One B-rep face of a CAD part: STEP entity #228.
In plain terms, the cylindrical face has radius 5 mm (diameter 10 mm), a partial arc.
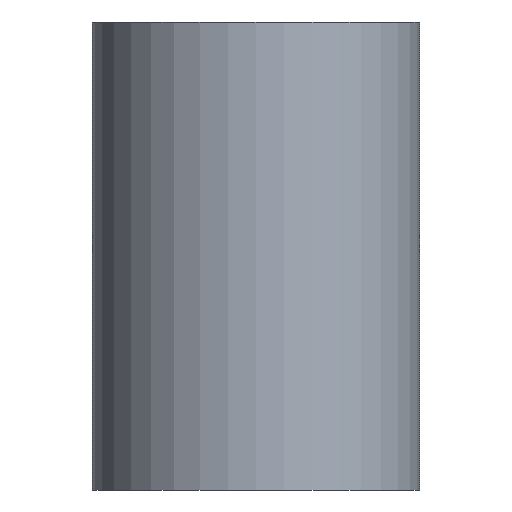
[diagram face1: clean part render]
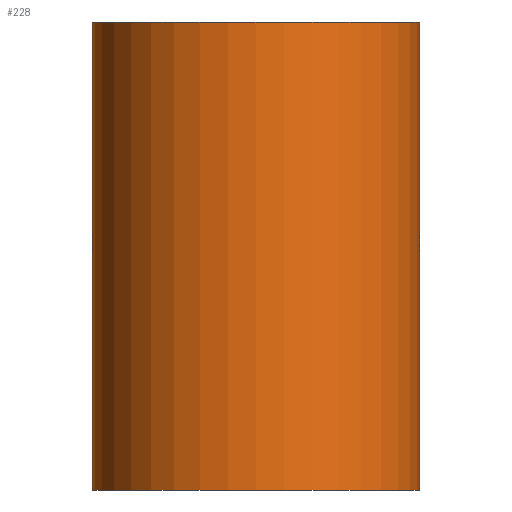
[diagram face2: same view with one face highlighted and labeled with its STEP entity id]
Its self-contained STEP definition (entity closure, numbers rounded to 3 decimals):
#44 = PLANE('',#45);
#45 = AXIS2_PLACEMENT_3D('',#46,#47,#48);
#46 = CARTESIAN_POINT('',(-22.5,5.,0.));
#47 = DIRECTION('',(0.,1.,0.));
#48 = DIRECTION('',(1.,0.,0.));
#73 = PLANE('',#74);
#74 = AXIS2_PLACEMENT_3D('',#75,#76,#77);
#75 = CARTESIAN_POINT('',(0.,0.,14.3));
#76 = DIRECTION('',(0.,0.,1.));
#77 = DIRECTION('',(1.,0.,-0.));
#105 = PLANE('',#106);
#106 = AXIS2_PLACEMENT_3D('',#107,#108,#109);
#107 = CARTESIAN_POINT('',(0.,-5.,0.));
#108 = DIRECTION('',(0.,1.,0.));
#109 = DIRECTION('',(1.,0.,0.));
#132 = PLANE('',#133);
#133 = AXIS2_PLACEMENT_3D('',#134,#135,#136);
#134 = CARTESIAN_POINT('',(0.,0.,0.));
#135 = DIRECTION('',(0.,0.,1.));
#136 = DIRECTION('',(1.,0.,-0.));
#153 = VERTEX_POINT('',#154);
#154 = CARTESIAN_POINT('',(-22.5,-5.,14.3));
#175 = EDGE_CURVE('',#153,#176,#178,.T.);
#176 = VERTEX_POINT('',#177);
#177 = CARTESIAN_POINT('',(-22.5,5.,14.3));
#178 = SURFACE_CURVE('',#179,(#184,#195),.PCURVE_S1.);
#179 = CIRCLE('',#180,5.);
#180 = AXIS2_PLACEMENT_3D('',#181,#182,#183);
#181 = CARTESIAN_POINT('',(-22.5,0.,14.3));
#182 = DIRECTION('',(0.,0.,-1.));
#183 = DIRECTION('',(1.,0.,0.));
#184 = PCURVE('',#73,#185);
#185 = DEFINITIONAL_REPRESENTATION('',(#186),#194);
#186 = ( BOUNDED_CURVE() B_SPLINE_CURVE(2,(#187,#188,#189,#190,#191,#192
,#193),.UNSPECIFIED.,.T.,.F.) B_SPLINE_CURVE_WITH_KNOTS((1,2,2,2,2,1),(
    -2.094,0.,2.094,4.189,6.283,
8.378),.UNSPECIFIED.) CURVE() GEOMETRIC_REPRESENTATION_ITEM() 
RATIONAL_B_SPLINE_CURVE((1.,0.5,1.,0.5,1.,0.5,1.)) REPRESENTATION_ITEM(
  '') );
#187 = CARTESIAN_POINT('',(-17.5,0.));
#188 = CARTESIAN_POINT('',(-17.5,-8.66));
#189 = CARTESIAN_POINT('',(-25.,-4.33));
#190 = CARTESIAN_POINT('',(-32.5,0.));
#191 = CARTESIAN_POINT('',(-25.,4.33));
#192 = CARTESIAN_POINT('',(-17.5,8.66));
#193 = CARTESIAN_POINT('',(-17.5,0.));
#194 = ( GEOMETRIC_REPRESENTATION_CONTEXT(2) 
PARAMETRIC_REPRESENTATION_CONTEXT() REPRESENTATION_CONTEXT('2D SPACE',''
  ) );
#195 = PCURVE('',#196,#201);
#196 = CYLINDRICAL_SURFACE('',#197,5.);
#197 = AXIS2_PLACEMENT_3D('',#198,#199,#200);
#198 = CARTESIAN_POINT('',(-22.5,0.,0.));
#199 = DIRECTION('',(0.,0.,-1.));
#200 = DIRECTION('',(1.,0.,0.));
#201 = DEFINITIONAL_REPRESENTATION('',(#202),#206);
#202 = LINE('',#203,#204);
#203 = CARTESIAN_POINT('',(0.,-14.3));
#204 = VECTOR('',#205,1.);
#205 = DIRECTION('',(1.,0.));
#206 = ( GEOMETRIC_REPRESENTATION_CONTEXT(2) 
PARAMETRIC_REPRESENTATION_CONTEXT() REPRESENTATION_CONTEXT('2D SPACE',''
  ) );
#228 = ADVANCED_FACE('',(#229),#196,.T.);
#229 = FACE_BOUND('',#230,.T.);
#230 = EDGE_LOOP('',(#231,#254,#255,#278));
#231 = ORIENTED_EDGE('',*,*,#232,.T.);
#232 = EDGE_CURVE('',#233,#153,#235,.T.);
#233 = VERTEX_POINT('',#234);
#234 = CARTESIAN_POINT('',(-22.5,-5.,0.));
#235 = SURFACE_CURVE('',#236,(#240,#247),.PCURVE_S1.);
#236 = LINE('',#237,#238);
#237 = CARTESIAN_POINT('',(-22.5,-5.,0.));
#238 = VECTOR('',#239,1.);
#239 = DIRECTION('',(0.,0.,1.));
#240 = PCURVE('',#196,#241);
#241 = DEFINITIONAL_REPRESENTATION('',(#242),#246);
#242 = LINE('',#243,#244);
#243 = CARTESIAN_POINT('',(1.571,0.));
#244 = VECTOR('',#245,1.);
#245 = DIRECTION('',(0.,-1.));
#246 = ( GEOMETRIC_REPRESENTATION_CONTEXT(2) 
PARAMETRIC_REPRESENTATION_CONTEXT() REPRESENTATION_CONTEXT('2D SPACE',''
  ) );
#247 = PCURVE('',#105,#248);
#248 = DEFINITIONAL_REPRESENTATION('',(#249),#253);
#249 = LINE('',#250,#251);
#250 = CARTESIAN_POINT('',(-22.5,0.));
#251 = VECTOR('',#252,1.);
#252 = DIRECTION('',(0.,-1.));
#253 = ( GEOMETRIC_REPRESENTATION_CONTEXT(2) 
PARAMETRIC_REPRESENTATION_CONTEXT() REPRESENTATION_CONTEXT('2D SPACE',''
  ) );
#254 = ORIENTED_EDGE('',*,*,#175,.T.);
#255 = ORIENTED_EDGE('',*,*,#256,.F.);
#256 = EDGE_CURVE('',#257,#176,#259,.T.);
#257 = VERTEX_POINT('',#258);
#258 = CARTESIAN_POINT('',(-22.5,5.,0.));
#259 = SURFACE_CURVE('',#260,(#264,#271),.PCURVE_S1.);
#260 = LINE('',#261,#262);
#261 = CARTESIAN_POINT('',(-22.5,5.,0.));
#262 = VECTOR('',#263,1.);
#263 = DIRECTION('',(0.,0.,1.));
#264 = PCURVE('',#196,#265);
#265 = DEFINITIONAL_REPRESENTATION('',(#266),#270);
#266 = LINE('',#267,#268);
#267 = CARTESIAN_POINT('',(4.712,0.));
#268 = VECTOR('',#269,1.);
#269 = DIRECTION('',(0.,-1.));
#270 = ( GEOMETRIC_REPRESENTATION_CONTEXT(2) 
PARAMETRIC_REPRESENTATION_CONTEXT() REPRESENTATION_CONTEXT('2D SPACE',''
  ) );
#271 = PCURVE('',#44,#272);
#272 = DEFINITIONAL_REPRESENTATION('',(#273),#277);
#273 = LINE('',#274,#275);
#274 = CARTESIAN_POINT('',(0.,0.));
#275 = VECTOR('',#276,1.);
#276 = DIRECTION('',(0.,-1.));
#277 = ( GEOMETRIC_REPRESENTATION_CONTEXT(2) 
PARAMETRIC_REPRESENTATION_CONTEXT() REPRESENTATION_CONTEXT('2D SPACE',''
  ) );
#278 = ORIENTED_EDGE('',*,*,#279,.F.);
#279 = EDGE_CURVE('',#233,#257,#280,.T.);
#280 = SURFACE_CURVE('',#281,(#286,#293),.PCURVE_S1.);
#281 = CIRCLE('',#282,5.);
#282 = AXIS2_PLACEMENT_3D('',#283,#284,#285);
#283 = CARTESIAN_POINT('',(-22.5,0.,0.));
#284 = DIRECTION('',(0.,0.,-1.));
#285 = DIRECTION('',(1.,0.,0.));
#286 = PCURVE('',#196,#287);
#287 = DEFINITIONAL_REPRESENTATION('',(#288),#292);
#288 = LINE('',#289,#290);
#289 = CARTESIAN_POINT('',(0.,0.));
#290 = VECTOR('',#291,1.);
#291 = DIRECTION('',(1.,0.));
#292 = ( GEOMETRIC_REPRESENTATION_CONTEXT(2) 
PARAMETRIC_REPRESENTATION_CONTEXT() REPRESENTATION_CONTEXT('2D SPACE',''
  ) );
#293 = PCURVE('',#132,#294);
#294 = DEFINITIONAL_REPRESENTATION('',(#295),#303);
#295 = ( BOUNDED_CURVE() B_SPLINE_CURVE(2,(#296,#297,#298,#299,#300,#301
,#302),.UNSPECIFIED.,.T.,.F.) B_SPLINE_CURVE_WITH_KNOTS((1,2,2,2,2,1),(
    -2.094,0.,2.094,4.189,6.283,
8.378),.UNSPECIFIED.) CURVE() GEOMETRIC_REPRESENTATION_ITEM() 
RATIONAL_B_SPLINE_CURVE((1.,0.5,1.,0.5,1.,0.5,1.)) REPRESENTATION_ITEM(
  '') );
#296 = CARTESIAN_POINT('',(-17.5,0.));
#297 = CARTESIAN_POINT('',(-17.5,-8.66));
#298 = CARTESIAN_POINT('',(-25.,-4.33));
#299 = CARTESIAN_POINT('',(-32.5,0.));
#300 = CARTESIAN_POINT('',(-25.,4.33));
#301 = CARTESIAN_POINT('',(-17.5,8.66));
#302 = CARTESIAN_POINT('',(-17.5,0.));
#303 = ( GEOMETRIC_REPRESENTATION_CONTEXT(2) 
PARAMETRIC_REPRESENTATION_CONTEXT() REPRESENTATION_CONTEXT('2D SPACE',''
  ) );
